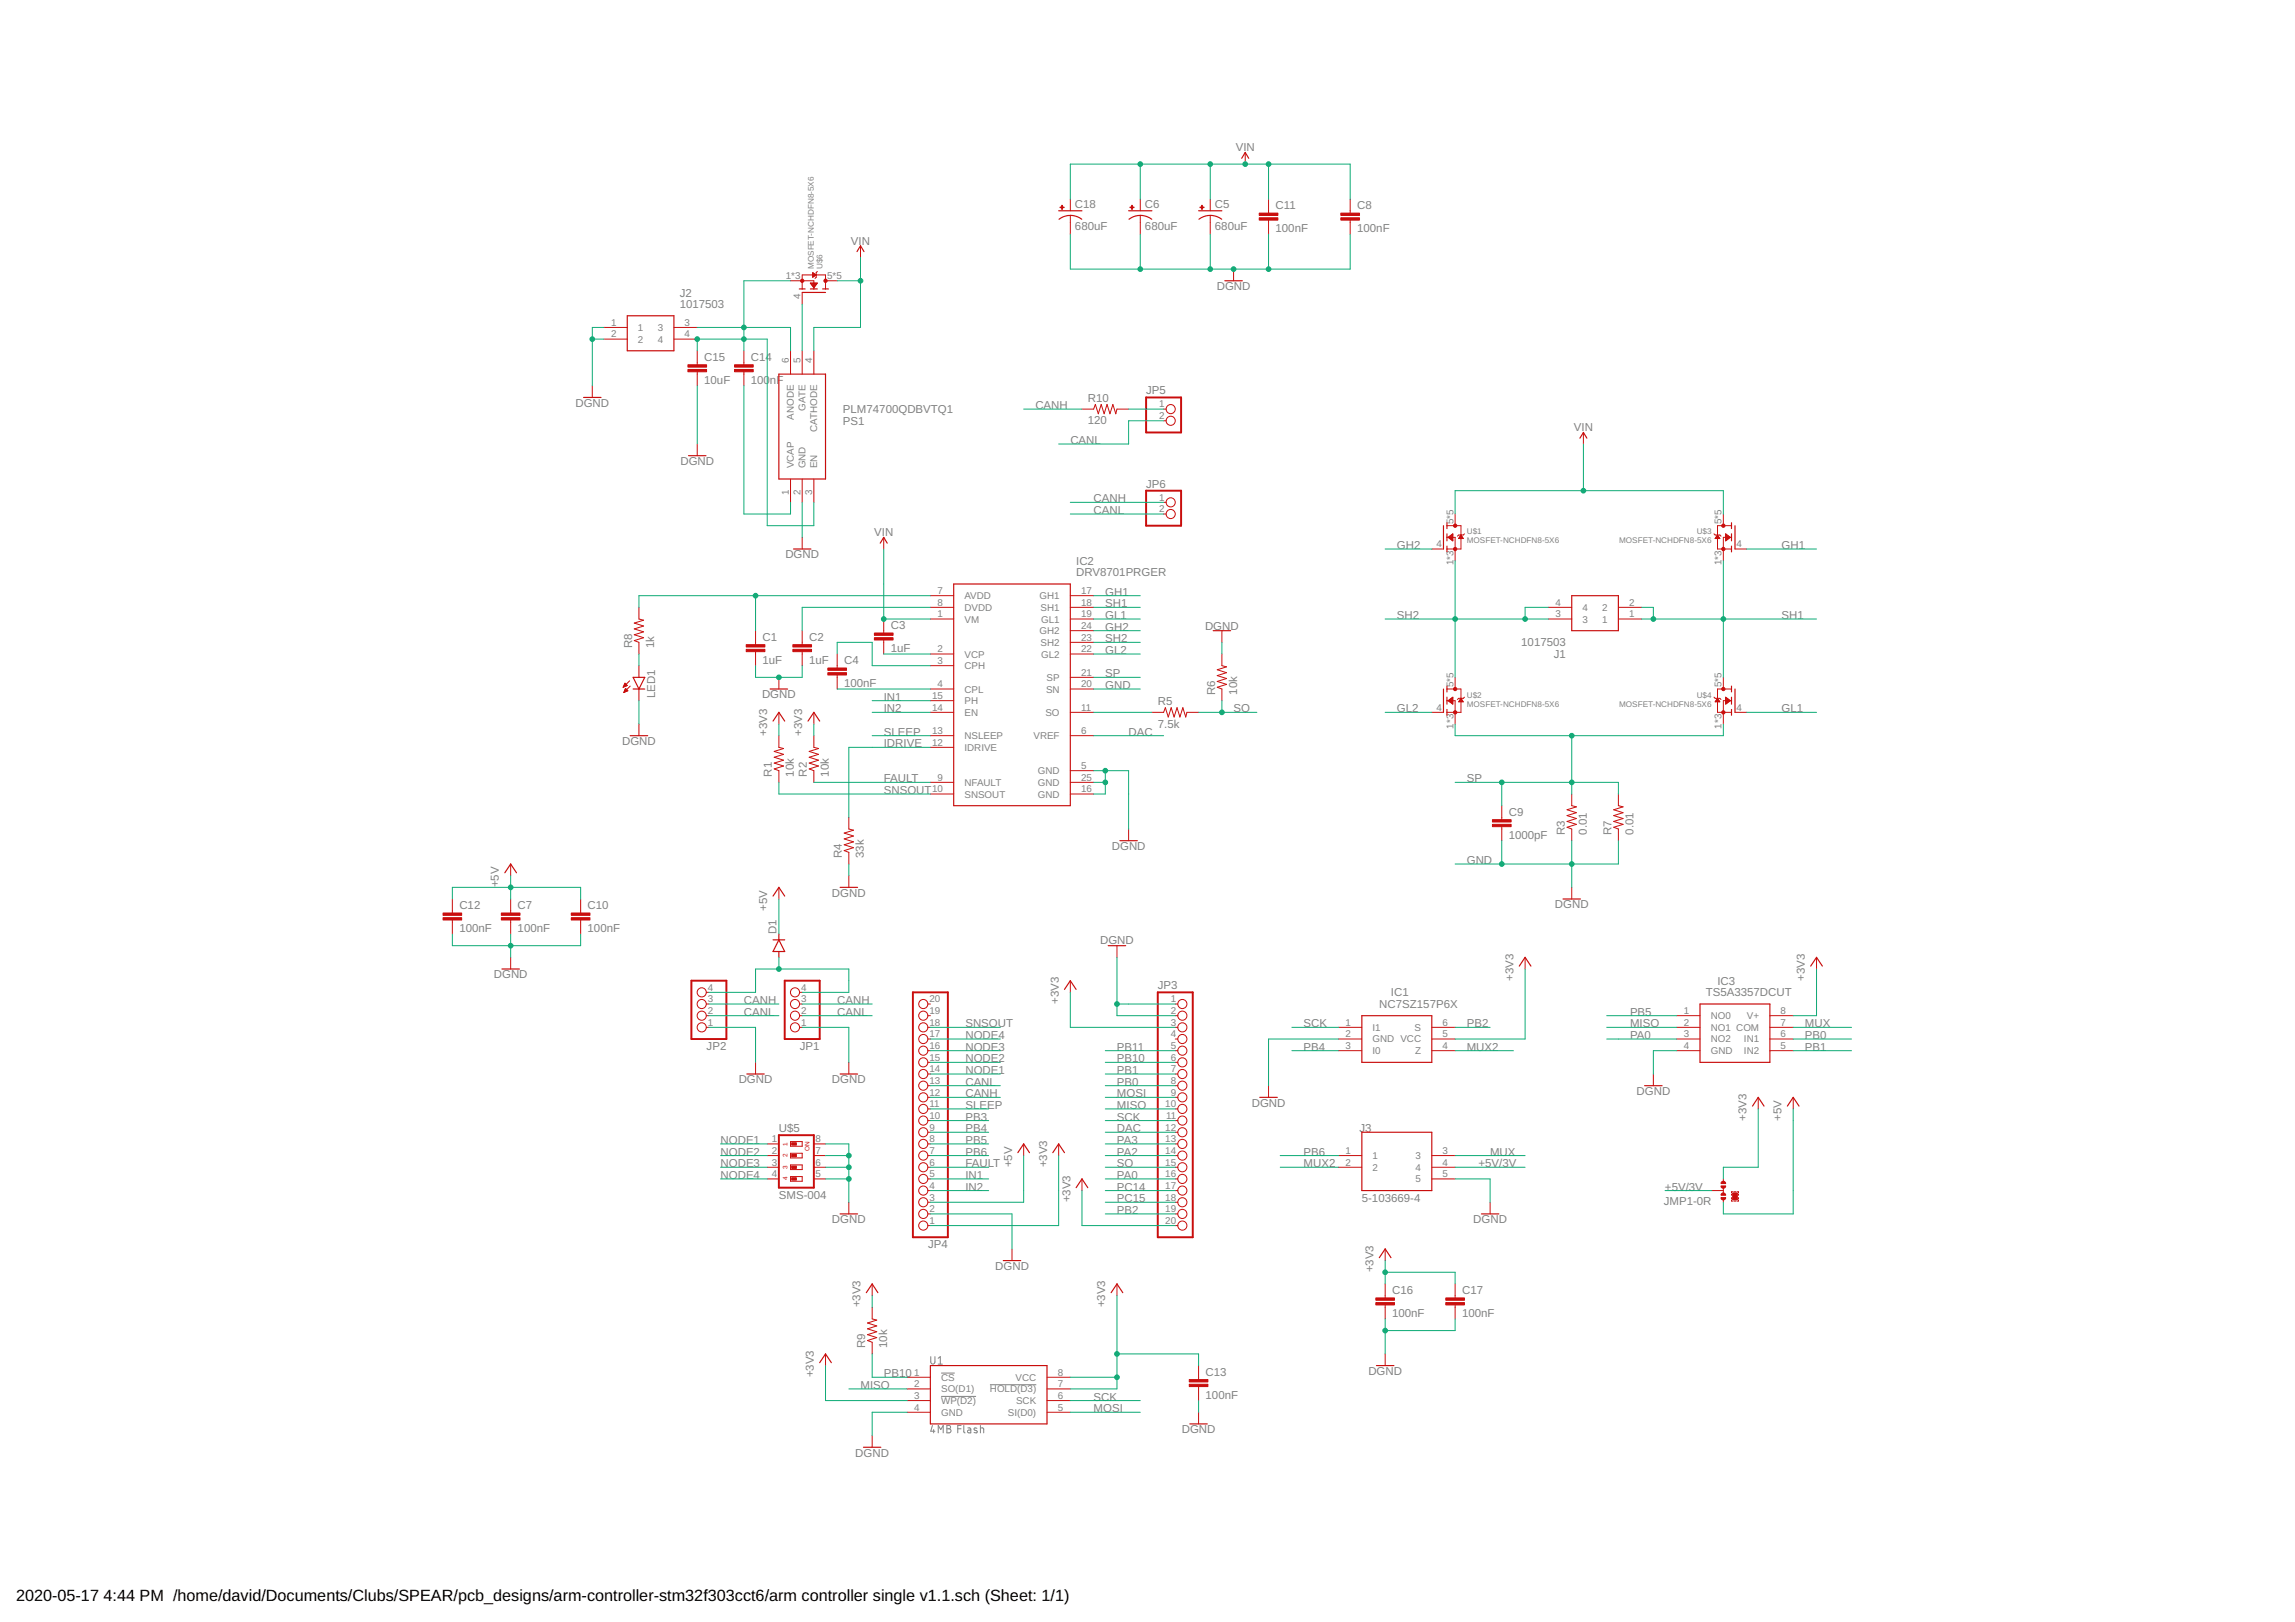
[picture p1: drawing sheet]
<svg xmlns="http://www.w3.org/2000/svg" width="500mm" height="353mm" viewBox="0 0 500 353" stroke-linecap="round" stroke-linejoin="round" font-family="sans-serif">
<defs><g id="words">
<g font-size="3.5">
<text x="3.5" y="348.6">2020-05-17</text>
<text x="22.6" y="348.6">4:44 PM /home/david/Documents/Clubs/SPEAR/pcb_designs/arm-controller-stm32f303cct6/arm controller single v1.1.sch (Sheet: 1/1)</text>
</g>
<g font-size="2.5" fill="#808080">
<text x="269.2" y="32.9">VIN</text>
<text x="234.2" y="45.3">C18</text>
<text x="249.4" y="45.3">C6</text>
<text x="264.6" y="45.3">C5</text>
<text x="277.8" y="45.5">C11</text>
<text x="295.6" y="45.5">C8</text>
<text x="185.3" y="53.3">VIN</text>
<text x="234.2" y="50.1">680uF</text>
<text x="249.4" y="50.1">680uF</text>
<text x="264.6" y="50.1">680uF</text>
<text x="277.8" y="50.6">100nF</text>
<text x="295.6" y="50.6">100nF</text>
<text x="148.1" y="64.6">J2</text>
<text x="265" y="63.2">DGND</text>
<text x="148.1" y="67.1">1017503</text>
<text x="153.4" y="83.6">10uF</text>
<text x="153.4" y="78.5">C15</text>
<text x="163.5" y="83.6">100</text>
<text x="163.5" y="78.5">C14</text>
<text x="167.7" y="83.6">nF</text>
<text x="125.3" y="88.6">DGND</text>
<text x="183.6" y="89.9">PLM74700QDBVTQ1</text>
<text x="225.5" y="89.1">CANH</text>
<text x="236.9" y="87.6">R10</text>
<text x="249.6" y="85.9">JP5</text>
<text x="183.6" y="92.5">PS1</text>
<text x="236.9" y="92.4">120</text>
<text x="342.8" y="93.9">VIN</text>
<text x="148.2" y="101.3">DGND</text>
<text x="233.1" y="96.7">CANL</text>
<text x="249.6" y="106.2">JP6</text>
<text x="238.2" y="109.4">CANH</text>
<text x="238.2" y="111.9">CANL</text>
<text x="190.4" y="116.7">VIN</text>
<text x="304.2" y="119.5">GH2</text>
<text x="388.1" y="119.5">GH1</text>
<text x="171.1" y="121.6">DGND</text>
<text x="234.4" y="125.5">DRV8701PRGER</text>
<text x="234.4" y="123">IC2</text>
<text x="240.8" y="129.7">GH1</text>
<text x="194" y="136.9">C3</text>
<text x="240.8" y="137.3">GH2</text>
<text x="240.8" y="134.8">GL1</text>
<text x="240.8" y="132.2">SH1</text>
<text x="262.5" y="137.1">DGND</text>
<text x="304.2" y="134.8">SH2</text>
<text x="388.1" y="134.8">SH1</text>
<text x="137.7" y="141.1" transform="rotate(-90 137.7 141.1)">R8</text>
<text x="142.5" y="141.1" transform="rotate(-90 142.5 141.1)">1k</text>
<text x="166.1" y="139.5">C1</text>
<text x="176.2" y="139.5">C2</text>
<text x="194" y="142">1uF</text>
<text x="240.8" y="142.4">GL2</text>
<text x="240.8" y="139.9">SH2</text>
<text x="331.4" y="140.7">1017503</text>
<text x="338.4" y="143.3">J1</text>
<text x="166.1" y="144.6">1uF</text>
<text x="176.2" y="144.6">1uF</text>
<text x="183.9" y="149.6">100nF</text>
<text x="183.9" y="144.6">C4</text>
<text x="240.8" y="147.5">SP</text>
<text x="142.7" y="152" transform="rotate(-90 142.7 152)">LED1</text>
<text x="166" y="152">DGND</text>
<text x="192.5" y="152.6">IN1</text>
<text x="192.5" y="155.1">IN2</text>
<text x="240.8" y="150">GND</text>
<text x="252.2" y="153.6">R5</text>
<text x="264.7" y="151.3" transform="rotate(-90 264.7 151.3)">R6</text>
<text x="268.7" y="155.1">SO</text>
<text x="269.5" y="151.3" transform="rotate(-90 269.5 151.3)">10k</text>
<text x="304.2" y="155.1">GL2</text>
<text x="388.1" y="155.1">GL1</text>
<text x="167.1" y="160.2" transform="rotate(-90 167.1 160.2)">+3V3</text>
<text x="174.7" y="160.2" transform="rotate(-90 174.7 160.2)">+3V3</text>
<text x="192.5" y="160.2">SLEEP</text>
<text x="245.8" y="160.2">DAC</text>
<text x="252.2" y="158.4">7.5k</text>
<text x="135.5" y="162.2">DGND</text>
<text x="192.5" y="162.7">IDRIVE</text>
<text x="168.1" y="169.1" transform="rotate(-90 168.1 169.1)">R1</text>
<text x="172.9" y="169.1" transform="rotate(-90 172.9 169.1)">10k</text>
<text x="175.8" y="169.1" transform="rotate(-90 175.8 169.1)">R2</text>
<text x="180.6" y="169.1" transform="rotate(-90 180.6 169.1)">10k</text>
<text x="192.5" y="170.3">FAULT</text>
<text x="192.5" y="172.9">SNSOUT</text>
<text x="319.5" y="170.3">SP</text>
<text x="328.6" y="177.6">C9</text>
<text x="242.2" y="185.1">DGND</text>
<text x="328.6" y="182.6">1000pF</text>
<text x="340.8" y="181.8" transform="rotate(-90 340.8 181.8)">R3</text>
<text x="345.6" y="181.8" transform="rotate(-90 345.6 181.8)">0.01</text>
<text x="351" y="181.8" transform="rotate(-90 351 181.8)">R7</text>
<text x="355.8" y="181.8" transform="rotate(-90 355.8 181.8)">0.01</text>
<text x="183.4" y="186.8" transform="rotate(-90 183.4 186.8)">R4</text>
<text x="188.2" y="186.8" transform="rotate(-90 188.2 186.8)">33k</text>
<text x="319.5" y="188.1">GND</text>
<text x="100.1" y="197.9">C12</text>
<text x="108.7" y="193.2" transform="rotate(-90 108.7 193.2)">+5V</text>
<text x="112.8" y="197.9">C7</text>
<text x="128" y="197.9">C10</text>
<text x="181.2" y="195.2">DGND</text>
<text x="338.7" y="197.8">DGND</text>
<text x="100.1" y="203">100nF</text>
<text x="112.8" y="203">100nF</text>
<text x="128" y="203">100nF</text>
<text x="167.1" y="198.3" transform="rotate(-90 167.1 198.3)">+5V</text>
<text x="169.2" y="203.3" transform="rotate(-90 169.2 203.3)">D1</text>
<text x="239.6" y="205.6">DGND</text>
<text x="107.6" y="213">DGND</text>
<text x="252.2" y="215.4">JP3</text>
<text x="329.6" y="213.5" transform="rotate(-90 329.6 213.5)">+3V3</text>
<text x="374.1" y="214.4">IC3</text>
<text x="393.1" y="213.5" transform="rotate(-90 393.1 213.5)">+3V3</text>
<text x="162" y="218.6">CANH</text>
<text x="162" y="221.1">CANL</text>
<text x="182.3" y="218.6">CANH</text>
<text x="182.3" y="221.1">CANL</text>
<text x="230.6" y="218.6" transform="rotate(-90 230.6 218.6)">+3V3</text>
<text x="300.4" y="219.5">NC7SZ157P6X</text>
<text x="303" y="216.9">IC1</text>
<text x="355" y="221.1">PB5</text>
<text x="371.6" y="216.9">TS5A3357DCUT</text>
<text x="210.3" y="226.2">NODE4</text>
<text x="210.3" y="223.7">SNSOUT</text>
<text x="283.9" y="223.7">SCK</text>
<text x="319.5" y="223.7">PB2</text>
<text x="355" y="226.2">PA0</text>
<text x="355" y="223.7">MISO</text>
<text x="393.1" y="223.7">MUX</text>
<text x="393.1" y="226.2">PB0</text>
<text x="153.9" y="228.6">JP2</text>
<text x="174.2" y="228.6">JP1</text>
<text x="210.3" y="233.8">NODE1</text>
<text x="210.3" y="231.3">NODE2</text>
<text x="210.3" y="228.7">NODE3</text>
<text x="243.3" y="233.8">PB1</text>
<text x="243.3" y="231.3">PB10</text>
<text x="243.3" y="228.7">PB11</text>
<text x="283.9" y="228.7">PB4</text>
<text x="319.5" y="228.7">MUX2</text>
<text x="393.1" y="228.7">PB1</text>
<text x="160.9" y="235.9">DGND</text>
<text x="181.2" y="235.9">DGND</text>
<text x="210.3" y="238.9">CANH</text>
<text x="210.3" y="236.4">CANL</text>
<text x="243.3" y="238.9">MOSI</text>
<text x="243.3" y="236.4">PB0</text>
<text x="356.5" y="238.4">DGND</text>
<text x="210.3" y="241.4">SLEEP</text>
<text x="210.3" y="244">PB3</text>
<text x="243.3" y="244">SCK</text>
<text x="243.3" y="241.4">MISO</text>
<text x="272.6" y="240.9">DGND</text>
<text x="380.4" y="244" transform="rotate(-90 380.4 244)">+3V3</text>
<text x="388.1" y="244" transform="rotate(-90 388.1 244)">+5V</text>
<text x="156.9" y="249.1">NODE1</text>
<text x="156.9" y="251.6">NODE2</text>
<text x="169.6" y="246.5">U$5</text>
<text x="210.3" y="246.5">PB4</text>
<text x="210.3" y="249.1">PB5</text>
<text x="210.3" y="251.6">PB6</text>
<text x="243.3" y="251.6">PA2</text>
<text x="243.3" y="249.1">PA3</text>
<text x="243.3" y="246.5">DAC</text>
<text x="283.9" y="251.6">PB6</text>
<text x="296.1" y="246.5">J</text>
<text x="297.4" y="246.5">3</text>
<text x="324.6" y="251.6">MUX</text>
<text x="156.9" y="254.1">NODE3</text>
<text x="156.9" y="256.7">NODE4</text>
<text x="210.3" y="256.7">IN1</text>
<text x="210.3" y="254.1">FAULT</text>
<text x="220.4" y="254.1" transform="rotate(-90 220.4 254.1)">+5V</text>
<text x="228.1" y="254.1" transform="rotate(-90 228.1 254.1)">+3V3</text>
<text x="243.3" y="254.1">SO</text>
<text x="243.3" y="256.7">PA0</text>
<text x="283.9" y="254.1">MUX2</text>
<text x="322" y="254.1">+5V/3V</text>
<text x="169.6" y="261.1">SMS-004</text>
<text x="210.3" y="259.2">IN2</text>
<text x="233.1" y="261.8" transform="rotate(-90 233.1 261.8)">+3V3</text>
<text x="243.3" y="259.2">PC14</text>
<text x="243.3" y="261.8">PC15</text>
<text x="296.6" y="261.8">5-103669-4</text>
<text x="362.4" y="262.3">JMP1-0R</text>
<text x="362.7" y="259.2">+5V/3V</text>
<text x="181.2" y="266.3">DGND</text>
<text x="243.3" y="264.3">PB2</text>
<text x="320.9" y="266.3">DGND</text>
<text x="202.2" y="271.8">JP4</text>
<text x="216.8" y="276.5">DGND</text>
<text x="299.2" y="277" transform="rotate(-90 299.2 277)">+3V3</text>
<text x="303.2" y="281.7">C16</text>
<text x="318.5" y="281.7">C17</text>
<text x="187.4" y="284.6" transform="rotate(-90 187.4 284.6)">+3V3</text>
<text x="240.8" y="284.6" transform="rotate(-90 240.8 284.6)">+3V3</text>
<text x="303.2" y="286.8">100nF</text>
<text x="318.5" y="286.8">100nF</text>
<text x="188.5" y="293.5" transform="rotate(-90 188.5 293.5)">R9</text>
<text x="193.3" y="293.5" transform="rotate(-90 193.3 293.5)">10k</text>
<text x="177.3" y="299.8" transform="rotate(-90 177.3 299.8)">+3V3</text>
<text x="192.5" y="299.8">PB10</text>
<text x="262.6" y="299.5">C13</text>
<text x="298" y="299.3">DGND</text>
<text x="187.4" y="302.4">MISO</text>
<text x="238.2" y="304.9">SCK</text>
<text x="262.6" y="304.5">100nF</text>
<text x="238.2" y="307.5">MOSI</text>
<text x="186.3" y="317.1">DGND</text>
<text x="257.4" y="312">DGND</text>
</g>
<g font-size="2.1" fill="#808080">
<text x="171.1" y="60.8">1*3</text>
<text x="174.4" y="65.2" transform="rotate(-90 174.4 65.2)">4</text>
<text x="180.2" y="60.8">5*5</text>
<text x="133.1" y="70.9">1</text>
<text x="149.1" y="70.9">3</text>
<text x="133.1" y="73.5">2</text>
<text x="139" y="72">1</text>
<text x="139" y="74.6">2</text>
<text x="143.3" y="72">3</text>
<text x="143.3" y="74.6">4</text>
<text x="149.1" y="73.5">4</text>
<text x="171.8" y="79.1" transform="rotate(-90 171.8 79.1)">6</text>
<text x="174.4" y="79.1" transform="rotate(-90 174.4 79.1)">5</text>
<text x="176.9" y="79.1" transform="rotate(-90 176.9 79.1)">4</text>
<text x="175.5" y="89.4" transform="rotate(-90 175.5 89.4)">GATE</text>
<text x="252.5" y="88.7">1</text>
<text x="172.9" y="91.4" transform="rotate(-90 172.9 91.4)">ANODE</text>
<text x="178" y="94.1" transform="rotate(-90 178 94.1)">CATHODE</text>
<text x="252.5" y="91.2">2</text>
<text x="172.9" y="102" transform="rotate(-90 172.9 102)">VCAP</text>
<text x="175.5" y="102" transform="rotate(-90 175.5 102)">GND</text>
<text x="178" y="102" transform="rotate(-90 178 102)">EN</text>
<text x="171.8" y="107.8" transform="rotate(-90 171.8 107.8)">1</text>
<text x="174.4" y="107.8" transform="rotate(-90 174.4 107.8)">2</text>
<text x="176.9" y="107.8" transform="rotate(-90 176.9 107.8)">3</text>
<text x="252.5" y="109">1</text>
<text x="252.5" y="111.6">2</text>
<text x="312.9" y="119.2">4</text>
<text x="316.6" y="114.1" transform="rotate(-90 316.6 114.1)">5*5</text>
<text x="375" y="114.1" transform="rotate(-90 375 114.1)">5*5</text>
<text x="378.3" y="119.2">4</text>
<text x="316.6" y="123.1" transform="rotate(-90 316.6 123.1)">1*3</text>
<text x="375" y="123.1" transform="rotate(-90 375 123.1)">1*3</text>
<text x="204.2" y="129.3">7</text>
<text x="204.2" y="131.9">8</text>
<text x="210.1" y="130.5">AVDD</text>
<text x="226.4" y="130.5">GH1</text>
<text x="235.5" y="131.9">18</text>
<text x="235.5" y="129.3">17</text>
<text x="338.8" y="131.9">4</text>
<text x="354.8" y="131.9">2</text>
<text x="204.2" y="134.4">1</text>
<text x="210.1" y="135.5">VM</text>
<text x="210.1" y="133">DVDD</text>
<text x="226.7" y="133">SH1</text>
<text x="226.8" y="135.5">GL1</text>
<text x="235.5" y="137">24</text>
<text x="235.5" y="134.4">19</text>
<text x="338.8" y="134.4">3</text>
<text x="344.7" y="135.5">3</text>
<text x="344.7" y="133">4</text>
<text x="349" y="135.5">1</text>
<text x="349" y="133">2</text>
<text x="354.8" y="134.4">1</text>
<text x="204.2" y="142">2</text>
<text x="210.1" y="143.2">VCP</text>
<text x="226.4" y="138.1">GH2</text>
<text x="226.7" y="140.6">SH2</text>
<text x="226.8" y="143.2">GL2</text>
<text x="235.5" y="139.5">23</text>
<text x="235.5" y="142">22</text>
<text x="204.2" y="144.6">3</text>
<text x="204.2" y="149.7">4</text>
<text x="210.1" y="145.7">CPH</text>
<text x="227.9" y="148.2">SP</text>
<text x="235.5" y="147.1">21</text>
<text x="235.5" y="149.7">20</text>
<text x="316.6" y="149.7" transform="rotate(-90 316.6 149.7)">5*5</text>
<text x="375" y="149.7" transform="rotate(-90 375 149.7)">5*5</text>
<text x="203" y="152.2">15</text>
<text x="203" y="154.7">14</text>
<text x="210.1" y="150.8">CPL</text>
<text x="210.1" y="153.3">PH</text>
<text x="210.1" y="155.9">EN</text>
<text x="227.7" y="155.9">SO</text>
<text x="227.8" y="150.8">SN</text>
<text x="235.5" y="154.7">11</text>
<text x="312.9" y="154.7">4</text>
<text x="378.3" y="154.7">4</text>
<text x="203" y="159.8">13</text>
<text x="210.1" y="160.9">NSLEEP</text>
<text x="225.1" y="160.9">VREF</text>
<text x="235.5" y="159.8">6</text>
<text x="316.6" y="158.7" transform="rotate(-90 316.6 158.7)">1*3</text>
<text x="375" y="158.7" transform="rotate(-90 375 158.7)">1*3</text>
<text x="203" y="162.4">12</text>
<text x="210.1" y="163.5">IDRIVE</text>
<text x="235.5" y="167.4">5</text>
<text x="203" y="172.5">10</text>
<text x="204.2" y="170">9</text>
<text x="210.1" y="171.1">NFAULT</text>
<text x="210.1" y="173.6">SNSOUT</text>
<text x="226.1" y="168.6">GND</text>
<text x="226.1" y="173.6">GND</text>
<text x="226.1" y="171.1">GND</text>
<text x="235.5" y="172.5">16</text>
<text x="235.5" y="170">25</text>
<text x="154.2" y="215.7">4</text>
<text x="174.5" y="215.7">4</text>
<text x="154.2" y="220.8">2</text>
<text x="154.2" y="218.2">3</text>
<text x="174.5" y="220.8">2</text>
<text x="174.5" y="218.2">3</text>
<text x="202.5" y="220.8">19</text>
<text x="202.5" y="218.2">20</text>
<text x="255" y="218.2">1</text>
<text x="255" y="220.8">2</text>
<text x="366.8" y="220.8">1</text>
<text x="372.6" y="221.9">NO0</text>
<text x="380.5" y="221.9">V+</text>
<text x="387.9" y="220.8">8</text>
<text x="154.2" y="223.3">1</text>
<text x="174.5" y="223.3">1</text>
<text x="202.5" y="225.8">17</text>
<text x="202.5" y="223.3">18</text>
<text x="255" y="223.3">3</text>
<text x="255" y="225.8">4</text>
<text x="293.1" y="223.3">1</text>
<text x="293.1" y="225.8">2</text>
<text x="299" y="224.4">I1</text>
<text x="299" y="227">GND VCC</text>
<text x="308.1" y="224.4">S</text>
<text x="314.2" y="223.3">6</text>
<text x="314.2" y="225.8">5</text>
<text x="366.8" y="223.3">2</text>
<text x="366.8" y="225.8">3</text>
<text x="372.6" y="224.4">NO1 COM</text>
<text x="372.6" y="227">NO2</text>
<text x="379.9" y="227">IN1</text>
<text x="387.9" y="223.3">7</text>
<text x="387.9" y="225.8">6</text>
<text x="202.5" y="233.5">14</text>
<text x="202.5" y="230.9">15</text>
<text x="202.5" y="228.4">16</text>
<text x="255" y="228.4">5</text>
<text x="255" y="230.9">6</text>
<text x="255" y="233.5">7</text>
<text x="293.1" y="228.4">3</text>
<text x="299" y="229.5">I0</text>
<text x="308.2" y="229.5">Z</text>
<text x="314.2" y="228.4">4</text>
<text x="366.8" y="228.4">4</text>
<text x="372.6" y="229.5">GND</text>
<text x="379.9" y="229.5">IN2</text>
<text x="387.9" y="228.4">5</text>
<text x="202.5" y="238.5">12</text>
<text x="202.5" y="236">13</text>
<text x="255" y="236">8</text>
<text x="255" y="238.5">9</text>
<text x="202.5" y="243.6">10</text>
<text x="202.5" y="241.1">11</text>
<text x="253.8" y="241.1">10</text>
<text x="254" y="243.6">11</text>
<text x="168.1" y="248.7">1</text>
<text x="168.1" y="251.2">2</text>
<text x="177.6" y="251.2">7</text>
<text x="177.6" y="248.7">8</text>
<text x="202.5" y="251.2">7</text>
<text x="202.5" y="248.7">8</text>
<text x="202.5" y="246.2">9</text>
<text x="253.8" y="246.2">12</text>
<text x="253.8" y="248.7">13</text>
<text x="253.8" y="251.2">14</text>
<text x="293.1" y="251.2">1</text>
<text x="314.2" y="251.2">3</text>
<text x="168.1" y="253.8">3</text>
<text x="168.1" y="256.3">4</text>
<text x="177.6" y="256.3">5</text>
<text x="177.6" y="253.8">6</text>
<text x="202.5" y="256.3">5</text>
<text x="202.5" y="253.8">6</text>
<text x="253.8" y="253.8">15</text>
<text x="253.8" y="256.3">16</text>
<text x="293.1" y="253.8">2</text>
<text x="299" y="252.4">1</text>
<text x="299" y="254.9">2</text>
<text x="308.3" y="252.4">3</text>
<text x="308.3" y="254.9">4</text>
<text x="308.3" y="257.4">5</text>
<text x="314.2" y="253.8">4</text>
<text x="314.2" y="256.3">5</text>
<text x="202.5" y="263.9">2</text>
<text x="202.5" y="261.4">3</text>
<text x="202.5" y="258.9">4</text>
<text x="253.8" y="258.9">17</text>
<text x="253.8" y="261.4">18</text>
<text x="253.8" y="263.9">19</text>
<text x="202.5" y="266.5">1</text>
<text x="253.8" y="266.5">20</text>
<text x="199.1" y="299.5">1</text>
<text x="230.4" y="299.5">8</text>
<text x="199.1" y="304.6">3</text>
<text x="199.1" y="302">2</text>
<text x="205" y="300.6">CS</text>
<text x="205" y="305.7">WP(D2)</text>
<text x="205" y="303.2">SO(D1)</text>
<text x="215.6" y="303.2">HOLD(D3)</text>
<text x="221.2" y="300.6">VCC</text>
<text x="221.3" y="305.7">SCK</text>
<text x="230.4" y="302">7</text>
<text x="230.4" y="304.6">6</text>
<text x="199.1" y="307.1">4</text>
<text x="205" y="308.2">GND</text>
<text x="219.5" y="308.2">SI(D0)</text>
<text x="230.4" y="307.1">5</text>
</g>
<g font-size="1.8" fill="#808080">
<text x="177.3" y="58.6" transform="rotate(-90 177.3 58.6)">MOSFET-NCHDFN8-5X6</text>
<text x="179.2" y="58.6" transform="rotate(-90 179.2 58.6)">U$6</text>
<text x="319.5" y="118.3">MOSFET-NCHDFN8-5X6</text>
<text x="319.5" y="116.4">U$1</text>
<text x="352.7" y="118.3">MOSFET-NCHDFN8-5X6</text>
<text x="369.6" y="116.4">U$3</text>
<text x="319.5" y="153.8">MOSFET-NCHDFN8-5X6</text>
<text x="319.5" y="151.9">U$2</text>
<text x="352.7" y="153.8">MOSFET-NCHDFN8-5X6</text>
<text x="369.6" y="151.9">U$4</text>
</g>
<g font-size="1.4" fill="#c90d0c">
<text x="171.5" y="251.9" transform="rotate(-90 171.5 251.9)">2</text>
<text x="171.5" y="249.6" transform="rotate(-90 171.5 249.6)">1</text>
<text x="176.4" y="250.5" transform="rotate(-90 176.4 250.5)">ON</text>
<text x="171.5" y="257" transform="rotate(-90 171.5 257)">4</text>
<text x="171.5" y="254.4" transform="rotate(-90 171.5 254.4)">3</text>
</g>
</g></defs>
<g fill="none" stroke="#808080" stroke-width=".22">
<path d="M202.7 295.4v1.1a.46 .46 0 0 0 .5 .5 .46 .46 0 0 0 .4-.5v-1.1M204.3 295.7l.5-.3v1.6M204.3 297h1M205 298.9h3M203.1 310.3l-.4 1.3h.9M203.4 311.2v.8M204.4 312v-1.7l.5 .9 .5-.9v1.7M205 304h7.6M206.2 310.3h.5a.36 .36 0 0 1 .4 .4 .36 .36 0 0 1-.4 .4 .44 .44 0 0 1 .5 .4 .44 .44 0 0 1-.5 .5h-.5zM206.2 311.1h.5M208.6 311.1h.7M209.3 310.3h-.7v1.7"/>
<path d="M209.9 310.3v1.4l.3 .3M210.8 310.9l.6 .1 .1 1-.7-.2v-.4l.7-.1M212.8 311l-.4-.1-.3 .2 .6 .4 .2 .3-.3 .2-.4-.1M213.6 310.9l.6 .1 .1 1M213.6 310.3v1.7M215.6 301.5h10.1"/>
</g>
<g fill="none" stroke="#c90d0c" stroke-width=".22">
<path d="M271.2 33.2v2.5M177 59.4l.8 .5-.8 .5zM177 59.9h.6M177 59.8h.7M177 59.7h.5M177 59.6h.4M177 59.5h.2M178 59.1l-.2 .3v1l-.3 .2M187.4 53.5v2.5M233.1 43.3v2.6M233.1 46.9v4.1M248.4 43.3v2.6"/>
<path d="M248.4 46.9v4.1M263.6 43.3v2.6M263.6 46.9v4.1M268.7 58.6v2.5M276.3 43.3v3.1M276.3 47.9v3.1M294.1 43.3v3.1M294.1 47.9v3.1M131.6 71.3h5M131.6 73.8h5M146.8 71.3h5.1M146.8 73.8h5.1"/>
<path d="M151.9 76.4v3M162 76.4v3M172.2 76.4v5M172.2 61.1h5.1v1.8M174.7 62.9v-3h5.1v3M174.7 63.7v2.5M174.7 76.4v5M176.5 61.6h1.5l-.7 1.1zM176.6 61.8h1.3M176.7 61.9h1.1M176.8 62h1M176.9 62.1h.8"/>
<path d="M177 62.2h.6M177 60.3h.1M177 60.2h.3M177 60.1h.5M177 62.4h.5M177.1 62.5h.3M177.2 62.6h.1M177.3 76.4v5M179.8 61.1h2.6M129 84v2.5M151.9 80.9v3.1M151.9 96.7v2.5"/>
<path d="M162 80.9v3.1M235.7 89.1h2.5l.4-1 .6 2 .7-2 .6 2 .6-2 .7 2 .6-2 .6 2 .3-1h2.5M253.4 89.1h.6M253.4 91.6h.6M344.9 94.1v2.6M172.2 104.3v5.1M174.7 104.3v5.1M174.7 117v2.5M177.3 104.3v5.1M192.5 117v2.5M253.4 109.4h.6M253.4 111.9h.6"/>
<path d="M311.9 119.5h2.5M315.2 117h1.7v5.1M315.2 114.4h3v5.1h-3M315.4 117h1M315.4 117l1-.8v1.6zM315.6 116.9h.8M315.6 117.1h.8M315.7 116.8h.7M315.8 117.2h.6M315.9 116.6h.5M315.9 117.4h.5M316.1 116.5h.3"/>
<path d="M316.1 117.5h.3M316.2 116.4h.2M316.2 117.6h.2M316.4 116.3h.1M316.4 117.7h.1M316.9 111.9v2.5M317.8 117.1h.8M317.9 117h.7M317.9 116.9h.6M318 116.8h.4M318.1 116.6h.2M318.2 116.5h.1"/>
<path d="M318.2 116.5l.5 .7h-1zM319 116.2l-.3 .3h-1l-.2 .2M373.3 116.2l.3 .3h1l.3 .2M373.7 117.1h.8M373.7 117h.7M373.8 116.9h.6M373.9 116.8h.4M374 116.6h.2M374.1 116.5h.1M374.1 116.5l.5 .7h-1zM375.4 111.9v2.5M375.9 117.2h.7"/>
<path d="M375.9 117.1h.8M375.9 117h1M375.9 116.9h.8M375.9 116.8h.7M375.9 116.6h.5M375.9 116.5h.4M375.9 117.7h.1M375.9 117.6h.2M375.9 117.5h.3M375.9 117.4h.5M375.9 116.4h.2M375.9 116.3h.1"/>
<path d="M375.9 116.2l1 .8-1 .8zM377.1 117h-1.7v5.1M377.1 114.4h-3v5.1h3M377.9 119.5h2.5M139.2 132.2v2.6l1 .2-2 .7 2 .6-2 .6 2 .7-2 .6 2 .6-2 .7 1 .3v2.6M164.6 137.3v3.1M174.7 137.3v3.1M192.5 134.8v3M192.5 139.3v3.1M202.6 134.8h5.1M202.6 129.7h5.1M202.6 132.2h5.1"/>
<path d="M233.1 134.8h5.1M233.1 129.7h5.1M233.1 132.2h5.1M233.1 137.3h5.1M233.1 139.8h5.1M266.1 137.3v2.5M337.3 134.8h5M337.3 132.2h5M352.5 134.8h5.1M352.5 132.2h5.1M135.8 149.6h.1M135.8 149.5h.3"/>
<path d="M135.9 149.3h.5M135.9 149.2h.7M135.9 150.7h.2M136 149.1h.5M136 150.5h.4M136 149h.4M136 150.4h.7M136.1 150.3h.6M136.1 148.8h.1M136.1 148.7l.5 .5-.9 .4zM136.1 150.2h.4M136.2 150.1h.2"/>
<path d="M136.2 149.9h.1M136.2 149.9l.6 .5-.9 .4zM137.1 148.2l-1.4 1.4M137.3 149.4l-1.4 1.4M139.2 144.9v2.6M139.2 150v2.5M139.2 157.6v2.6M164.6 141.9v3M169.7 147.5v2.5M169.7 155.1v2.5M174.7 141.9v3M177.3 155.1v2.5"/>
<path d="M182.4 142.4v3M182.4 147v3M202.6 142.4h5.1M202.6 144.9h5.1M202.6 150h5.1M202.6 155.1h5.1M202.6 152.5h5.1M233.1 142.4h5.1M233.1 150h5.1M233.1 155.1h5.1M233.1 147.5h5.1M250.9 155.1h2.5l.4-1 .7 2 .6-2 .6 2 .7-2 .6 2 .6-2 .7 2 .2-1h2.6"/>
<path d="M266.1 142.4v2.5l1.1 .3-2.1 .6 2.1 .7-2.1 .6 2.1 .6-2.1 .7 2.1 .6-2.1 .6 1 .4v2.5M311.9 155.1h2.5M315.2 150h3v5.1h-3M315.2 152.5h1.7v5.1M315.4 152.5l1-.7v1.5zM315.5 152.6h.9M315.5 152.5h.9M315.6 152.7h.8M315.7 152.4h.7M315.8 152.8h.6M315.8 152.2h.6M316 153h.4"/>
<path d="M316 152.1h.4M316.1 153.1h.3M316.2 152h.2M316.3 153.2h.1M316.3 151.9h.1M316.9 147.5v2.5M317.8 152.7h.9M317.9 152.6h.7M317.9 152.5h.6M318 152.4h.4M318.1 152.2h.2M318.2 152.1h.1"/>
<path d="M318.2 152l.5 .8h-1zM319 151.8l-.3 .2h-1l-.2 .3M373.3 151.8l.3 .2h1l.3 .3M373.7 152.7h.8M373.7 152.6h.8M373.8 152.5h.6M373.9 152.4h.4M374 152.2h.2M374.1 152.1h.1M374.1 152l.5 .8h-1zM375.4 147.5v2.5M375.9 152.8h.6"/>
<path d="M375.9 152.7h.8M375.9 152.6h.9M375.9 152.5h.9M375.9 152.4h.7M375.9 152.2h.5M375.9 152.1h.4M375.9 153.2h.1M375.9 153.1h.3M375.9 153h.4M375.9 152h.2M375.9 151.9h.1M375.9 151.8l1 .7-1 .8z"/>
<path d="M377.1 152.5h-1.7v5.1M377.1 150h-3v5.1h3M377.9 155.1h2.5M169.7 160.2v2.5l1 .3-2.1 .6 2.1 .6-2.1 .7 2.1 .6-2.1 .6 2.1 .7-2.1 .6 1.1 .4v2.5M177.3 160.2v2.5l1 .3-2 .6 2 .6-2 .7 2 .6-2 .6 2 .7-2 .6 1 .4v2.5M184.9 177.9v2.6l1 .2-2 .7 2 .6-2 .6 2 .7-2 .6 2 .7-2 .6 1 .4v2.5M202.6 160.2h5.1M202.6 170.3h5.1M202.6 172.9h5.1M202.6 162.7h5.1M233.1 167.8h5.1M233.1 160.2h5.1"/>
<path d="M233.1 170.3h5.1M233.1 172.9h5.1M327.1 175.4v3.1M327.1 180v3M342.3 172.9v2.5l1.1 .3-2.1 .6 2.1 .6-2.1 .7 2.1 .6-2.1 .6 2.1 .7-2.1 .6 1 .4v2.5M352.5 172.9v2.5l1 .3-2 .6 2 .6-2 .7 2 .6-2 .6 2 .7-2 .6 1 .4v2.5M98.5 195.7v3.1M111.2 188.1v2.5M111.2 195.7v3.1M126.5 195.7v3.1M169.7 193.2v2.5M184.9 190.6v2.6"/>
<path d="M245.8 180.5v2.5M342.3 193.2v2.5M98.5 200.3v3M111.2 200.3v3M111.2 208.4v2.6M126.5 200.3v3M153.8 218.6h.6M153.8 216h.6M174.2 218.6h.5M174.2 216h.5M202.1 218.6h.5M233.1 213.5v2.5"/>
<path d="M243.3 205.9v2.5M256 218.6h.6M332.2 208.4v2.6M395.7 208.4v2.6M153.8 223.7h.6M153.8 221.1h.6M164.6 231.3v2.5M174.2 223.7h.5M174.2 221.1h.5M184.9 231.3v2.5M202.1 223.7h.5M202.1 221.1h.5"/>
<path d="M202.1 226.2h.5M202.1 228.7h.5M202.1 231.3h.5M202.1 233.8h.5M202.1 236.4h.5M202.1 238.9h.5M256 223.7h.6M256 221.1h.6M256 226.2h.6M256 228.7h.6M256 231.3h.6M256 233.8h.6"/>
<path d="M256 236.4h.6M256 238.9h.6M276.3 236.4v2.5M291.5 223.7h5.1M291.5 226.2h5.1M291.5 228.7h5.1M311.9 223.7h5M311.9 226.2h5M311.9 228.7h5M360.1 233.8v2.6M365.2 223.7h5.1M365.2 221.1h5.1"/>
<path d="M365.2 226.2h5.1M365.2 228.7h5.1M383 238.9v2.5M385.5 223.7h5.1M385.5 221.1h5.1M385.5 226.2h5.1M385.5 228.7h5.1M390.6 238.9v2.5M167.1 251.6h2.6M167.1 254.1h2.6M167.1 256.7h2.6M167.1 249h2.6"/>
<path d="M172.2 248.5h2.5v1.1h-2.5zM172.2 251.1h2.5v1h-2.5zM172.2 253.6h2.5v1h-2.5zM172.2 256.2h2.5v1h-2.5zM177.3 251.6h2.5M177.3 254.1h2.5M177.3 256.7h2.5M177.3 249h2.5M202.1 251.6h.5M202.1 254.1h.5M202.1 256.7h.5M202.1 259.2h.5"/>
<path d="M202.1 241.4h.5M202.1 244h.5M202.1 246.5h.5M202.1 249h.5M223 249v2.6M230.6 249v2.6M235.7 256.7v2.5M256 251.6h.6M256 254.1h.6M256 256.7h.6M256 259.2h.6M256 241.4h.6"/>
<path d="M256 244h.6M256 246.5h.6M256 249h.6M291.5 251.6h5.1M291.5 254.1h5.1M311.9 251.6h5M311.9 254.1h5M311.9 256.7h5M372.8 259.2h2.6M375.4 256.7v.7M375.4 258.7v1M377.1 260v.2"/>
<path d="M377.4 259.5h-.3v.2M377.7 259.5h.5M378.4 259.5h.3v.2M378.7 260v.2M184.9 261.7v2.6M190 279.5v2.6M202.1 261.7h.5M202.1 264.3h.5M202.1 266.8h.5M220.4 271.9v2.5M243.3 279.5v2.6M256 261.7h.6"/>
<path d="M256 264.3h.6M256 266.8h.6M301.7 271.9v2.5M301.7 279.5v3.1M316.9 279.5v3.1M324.6 261.7v2.6M375.4 261v.7M377.1 261.2v.3h.3M377.1 260.7v.3M377.7 261.5h.5M378.7 261.2v.3h-.3M378.7 260.7v.3"/>
<path d="M179.8 294.8v2.5M190 284.6v2.5l1 .3-2 .6 2 .7-2 .6 2 .6-2 .7 2 .6-2 .6 1 .4v2.6M197.6 299.8h5M228 299.8h5.1M261.1 297.3v3.1M301.7 284.1v3M301.7 294.8v2.5M316.9 284.1v3M190 312.5v2.6M197.6 304.9h5M197.6 307.5h5M197.6 302.4h5"/>
<path d="M228 304.9h5.1M228 307.5h5.1M228 302.4h5.1M261.1 301.9v3M261.1 307.5v2.5"/>
<circle cx="255" cy="91.6" r=".99"/>
<circle cx="255" cy="89.1" r=".99"/>
<circle cx="255" cy="109.4" r=".99"/>
<circle cx="255" cy="111.9" r=".99"/>
<circle cx="152.8" cy="218.6" r=".99"/>
<circle cx="152.8" cy="216" r=".99"/>
<circle cx="173.2" cy="218.6" r=".99"/>
<circle cx="173.2" cy="216" r=".99"/>
<circle cx="201.1" cy="218.6" r=".99"/>
<circle cx="257.5" cy="218.6" r=".99"/>
<circle cx="152.8" cy="223.7" r=".99"/>
<circle cx="152.8" cy="221.1" r=".99"/>
<circle cx="173.2" cy="223.7" r=".99"/>
<circle cx="173.2" cy="221.1" r=".99"/>
<circle cx="201.1" cy="228.7" r=".99"/>
<circle cx="201.1" cy="238.9" r=".99"/>
<circle cx="201.1" cy="236.4" r=".99"/>
<circle cx="201.1" cy="226.2" r=".99"/>
<circle cx="201.1" cy="233.8" r=".99"/>
<circle cx="201.1" cy="231.3" r=".99"/>
<circle cx="201.1" cy="223.7" r=".99"/>
<circle cx="201.1" cy="221.1" r=".99"/>
<circle cx="257.5" cy="223.7" r=".99"/>
<circle cx="257.5" cy="226.2" r=".99"/>
<circle cx="257.5" cy="236.4" r=".99"/>
<circle cx="257.5" cy="228.7" r=".99"/>
<circle cx="257.5" cy="231.3" r=".99"/>
<circle cx="257.5" cy="233.8" r=".99"/>
<circle cx="257.5" cy="221.1" r=".99"/>
<circle cx="257.5" cy="238.9" r=".99"/>
<circle cx="201.1" cy="246.5" r=".99"/>
<circle cx="201.1" cy="241.4" r=".99"/>
<circle cx="201.1" cy="251.6" r=".99"/>
<circle cx="201.1" cy="249" r=".99"/>
<circle cx="201.1" cy="259.2" r=".99"/>
<circle cx="201.1" cy="254.1" r=".99"/>
<circle cx="201.1" cy="256.7" r=".99"/>
<circle cx="201.1" cy="244" r=".99"/>
<circle cx="257.5" cy="246.5" r=".99"/>
<circle cx="257.5" cy="256.7" r=".99"/>
<circle cx="257.5" cy="259.2" r=".99"/>
<circle cx="257.5" cy="241.4" r=".99"/>
<circle cx="257.5" cy="244" r=".99"/>
<circle cx="257.5" cy="251.6" r=".99"/>
<circle cx="257.5" cy="254.1" r=".99"/>
<circle cx="257.5" cy="249" r=".99"/>
<circle cx="201.1" cy="266.8" r=".99"/>
<circle cx="201.1" cy="261.7" r=".99"/>
<circle cx="201.1" cy="264.3" r=".99"/>
<circle cx="257.5" cy="264.3" r=".99"/>
<circle cx="257.5" cy="266.8" r=".99"/>
<circle cx="257.5" cy="261.7" r=".99"/>
</g>
<g fill="#c90d0c" stroke="#c90d0c" stroke-width=".22">
<path d="M274.3 47.4h4v.5h-4z"/>
<path d="M274.3 46.4h4v.5h-4z"/>
<path d="M377.4 259.7h1v1.5h-1z"/>
<path d="M172.4 248.8h1.1v.5h-1.1z"/>
<path d="M172.4 251.3h1.1v.5h-1.1z"/>
<path d="M172.4 253.9h1.1v.5h-1.1z"/>
<path d="M172.4 256.4h1.1v.5h-1.1z"/>
<path d="M162.5 141.4h4.1v.5h-4.1z"/>
<path d="M162.5 140.4h4.1v.5h-4.1z"/>
<path d="M172.7 141.4h4.1v.5h-4.1z"/>
<path d="M172.7 140.4h4.1v.5h-4.1z"/>
<path d="M190.5 138.8h4v.5h-4z"/>
<path d="M190.5 137.8h4v.5h-4z"/>
<path d="M180.3 146.5h4.1v.5h-4.1z"/>
<path d="M180.3 145.4h4.1v.5h-4.1z"/>
<path d="M292.1 47.4h4v.5h-4z"/>
<path d="M292.1 46.4h4v.5h-4z"/>
<path d="M325.1 179.5h4v.5h-4z"/>
<path d="M325.1 178.5h4v.5h-4z"/>
<path d="M261.4 45.1h.9v.1h-.9z"/>
<path d="M261.7 44.7h.2v.9h-.2z"/>
<path d="M246.1 45.1h.9v.1h-.9z"/>
<path d="M246.5 44.7h.1v.9h-.1z"/>
<path d="M109.2 199.8h4.1v.5h-4.1z"/>
<path d="M109.2 198.8h4.1v.5h-4.1z"/>
<path d="M124.4 199.8h4.1v.5h-4.1z"/>
<path d="M124.4 198.8h4.1v.5h-4.1z"/>
<path d="M96.5 199.8h4.1v.5h-4.1z"/>
<path d="M96.5 198.8h4.1v.5h-4.1z"/>
<path d="M259 301.4h4.1v.5h-4.1z"/>
<path d="M259 300.4h4.1v.5h-4.1z"/>
<path d="M160 80.4h4.1v.5h-4.1z"/>
<path d="M160 79.4h4.1v.5h-4.1z"/>
<path d="M149.8 80.4h4.1v.5h-4.1z"/>
<path d="M149.8 79.4h4.1v.5h-4.1z"/>
<path d="M299.7 283.6h4v.5h-4z"/>
<path d="M299.7 282.6h4v.5h-4z"/>
<path d="M314.9 283.6h4.1v.5h-4.1z"/>
<path d="M314.9 282.6h4.1v.5h-4.1z"/>
<path d="M230.9 45.1h.9v.1h-.9z"/>
<path d="M231.3 44.7h.1v.9h-.1z"/>
</g>
<g fill="none" stroke="#c90d0c" stroke-width=".25">
<path d="M270.5 34.5l.7-1.3 .8 1.3M186.7 54.8l.7-1.3 .8 1.3M230.6 45.9h5.1M230.7 47.7a4 4 0 0 1 4.9 0M245.8 45.9h5.1M245.9 47.7a4 4 0 0 1 5 0M261.1 45.9h5M261.2 47.7a4 4 0 0 1 4.9 0M136.6 68.7h10.2v7.7h-10.2zM174.1 62.9h1.3M174.7 63.7h5.1M176.5 62.9h1.5"/>
<path d="M179.2 62.9h1.2M266.8 61.1h3.8M127.1 86.5h3.8M150 99.2h3.8M169.7 81.4h10.1v22.9h-10.1zM344.1 95.4l.8-1.3 .8 1.3M172.8 119.5h3.8M191.7 118.3l.8-1.3 .8 1.3M314.4 114.4v5.1M315.2 113.8v1.3M315.2 116.2v1.6M315.2 118.9v1.3"/>
<path d="M377.1 113.8v1.3M377.1 116.2v1.6M377.1 118.9v1.3M377.9 114.4v5.1M207.7 127.1h25.4v48.3h-25.4zM264.2 137.3h3.9M342.3 129.7h10.2v7.6h-10.2zM137.9 150h2.5M137.9 147.5h2.5l-1.2 2.5zM167.7 150h3.9M168.4 157l1.3-1.9 1.2 1.9M176 157l1.3-1.9 1.2 1.9"/>
<path d="M314.4 150v5.1M315.2 149.4v1.2M315.2 151.8v1.5M315.2 154.5v1.2M377.1 149.4v1.2M377.1 151.8v1.5M377.1 154.5v1.2M377.9 150v5.1M137.3 160.2h3.8M110 190l1.2-1.9 1.3 1.9M168.4 195.1l1.3-1.9 1.2 1.9M183 193.2h3.8"/>
<path d="M243.9 183h3.8M340.4 195.7h3.9M109.3 211h3.8M168.4 204.6h2.5M169.7 204.6l1.2 2.6h-2.5zM169.7 203.3v1.3M169.7 207.2v1.2M231.9 215.4l1.2-1.9 1.3 1.9M241.4 205.9h3.8M330.9 210.3l1.3-1.9 1.3 1.9M370.3 218.6h15.2v12.7h-15.2zM394.4 210.3l1.3-1.9 1.2 1.9"/>
<path d="M162.7 233.8h3.8M183 233.8h3.8M274.4 238.9h3.8M296.6 221.1h15.3v10.2h-15.3zM358.2 236.4h3.8M221.7 251l1.3-2 1.2 2M229.3 251l1.3-2 1.3 2M234.4 258.6l1.3-1.9 1.2 1.9M296.6 246.5h15.3v12.7h-15.3zM381.7 240.8l1.3-1.9 1.2 1.9M389.3 240.8l1.3-1.9 1.3 1.9M183 264.3h3.8"/>
<path d="M218.5 274.4h3.8M300.4 273.8l1.3-1.9 1.3 1.9M322.7 264.3h3.8M178.5 296.7l1.3-1.9 1.3 1.9M188.7 281.4l1.3-1.9 1.2 1.9M202.6 297.3h25.4v12.7h-25.4zM242 281.4l1.3-1.9 1.3 1.9M299.8 297.3h3.8M188.1 315.1h3.8M259.2 310h3.8"/>
</g>
<path d="M249.6 86.5h7.7v7.6h-7.7zM249.6 106.8h7.7v7.6h-7.7zM150.6 213.5h7.6v12.7h-7.6zM170.9 213.5h7.6v12.7h-7.6zM198.8 216h7.7v53.4h-7.7zM252.2 216h7.6v53.4h-7.6zM169.7 247.1h7.6v11.5h-7.6z" fill="none" stroke="#c90d0c" stroke-width=".42"/>
<g fill="#c90d0c" stroke="#c90d0c" stroke-width=".22">
<path d="M374.9 260.7h1a.51 .51 0 0 1-.5 .6 .51 .51 0 0 1-.5-.6z" fill-rule="evenodd"/>
<path d="M374.9 258.2h1a.51 .51 0 0 1-.5 .5 .51 .51 0 0 1-.5-.5z" fill-rule="evenodd"/>
<path d="M375 259.8l.5-.1 .4 .5h-1z" fill-rule="evenodd"/>
<path d="M375 257.3l.5-.1 .4 .5h-1z" fill-rule="evenodd"/>
<circle cx="316.9" cy="119.5" r=".36"/>
<circle cx="316.9" cy="114.4" r=".36"/>
<circle cx="316.9" cy="155.1" r=".36"/>
<circle cx="316.9" cy="150" r=".36"/>
<circle cx="375.4" cy="119.5" r=".36"/>
<circle cx="375.4" cy="114.4" r=".36"/>
<circle cx="375.4" cy="155.1" r=".36"/>
<circle cx="375.4" cy="150" r=".36"/>
<circle cx="174.7" cy="61.1" r=".36"/>
<circle cx="179.8" cy="61.1" r=".36"/>
</g>
<g fill="none" stroke="#0dab76" stroke-width=".22">
<path d="M248.4 35.7v7.6M263.6 35.7v7.6M276.3 35.7v7.6M187.4 56v15.3h-10.1v5.1M233.1 43.3v-7.6h61v7.6M233.1 51v7.6h61v-7.6M248.4 51v7.6M263.6 51v7.6M276.3 51v7.6M129 73.8h2.6M131.6 71.3h-2.6v12.7M151.9 76.4v-2.6h15.2v40.6h10.2v-5"/>
<path d="M151.9 71.3h20.3v5.1M172.2 61.1h-10.2v15.3M174.7 66.2v10.2M182.4 61.1h5M151.9 84v12.7M162 84v27.9h10.2v-2.5M223 89.1h12.7M245.8 89.1h7.6M253.4 91.6h-7.6v5.1h-15.2M344.9 96.7v10.1M174.7 109.4v7.6M192.5 119.5v15.3h10.1"/>
<path d="M233.1 109.4h20.3M233.1 111.9h20.3M301.7 119.5h10.2M316.9 111.9v-5.1h58.5v5.1M380.4 119.5h15.3M164.6 129.7v7.6M202.6 132.2h-27.9v5.1M202.6 129.7h-63.4v2.5M238.2 134.8h10.2M238.2 129.7h10.2M238.2 132.2h10.2M238.2 139.8h10.2"/>
<path d="M238.2 137.3h10.2M266.1 139.8v2.6M301.7 134.8h35.6M316.9 122.1v25.4M337.3 132.2h-5.1v2.6M357.6 132.2h2.5v2.6M357.6 134.8h38.1M375.4 122.1v25.4M139.2 142.4v2.5M139.2 152.5v5.1M164.6 144.9v2.6h10.1v-2.6M169.7 157.6v2.6"/>
<path d="M177.3 157.6v2.6M182.4 142.4v-2.6h7.6v5.1h12.6M182.4 150h20.2M190 152.5h12.6M190 155.1h12.6M192.5 142.4h10.1M238.2 147.5h10.2M238.2 150h10.2M238.2 155.1h12.7M238.2 142.4h10.2M261.1 155.1h12.7M266.1 152.5v2.6"/>
<path d="M301.7 155.1h10.2M316.9 157.6v2.6h58.5v-2.6M380.4 155.1h15.3M169.7 170.3v2.6h32.9M177.3 170.3h25.3M190 160.2h12.6M202.6 162.7h-17.7v15.2M238.2 167.8h7.6v12.7M238.2 170.3h2.5M238.2 160.2h15.2M240.7 167.8v5.1h-2.5M316.9 170.3h35.6v2.6"/>
<path d="M327.1 170.3v5.1M342.3 160.2v12.7M98.5 195.7v-2.5h28v2.5M111.2 190.6v5.1M169.7 195.7v7.6M184.9 188.1v2.5M327.1 183v5.1M342.3 183v10.2M352.5 183v5.1h-35.6M98.5 203.3v2.6h28v-2.6M111.2 203.3v5.1M154.4 216h10.2v-5h20.3v5h-10.2"/>
<path d="M154.4 218.6h15.3M169.7 208.4v2.6M174.7 218.6h15.3M233.1 216v7.7h22.9M243.3 208.4v12.7h12.7M243.3 218.6h12.7M332.2 211v15.2h-15.3M395.7 211v10.1h-5.1M154.4 223.7h10.2v7.6M154.4 221.1h15.3M174.7 223.7h10.2v7.6M174.7 221.1h15.3"/>
<path d="M202.6 223.7h15.3M202.6 226.2h15.3M202.6 228.7h15.3M202.6 238.9h15.3M202.6 236.4h15.3M202.6 233.8h15.3M202.6 231.3h15.3M240.7 228.7h15.3M240.7 238.9h15.3M240.7 236.4h15.3M240.7 233.8h15.3M240.7 231.3h15.3"/>
<path d="M281.4 223.7h10.1M281.4 228.7h10.1M291.5 226.2h-15.2v10.2M316.9 223.7h7.7M316.9 228.7h12.7M350 223.7h15.2M350 226.2h15.2M350 221.1h15.2M365.2 228.7h-5.1v5.1M390.6 223.7h12.7M390.6 226.2h12.7M390.6 228.7h12.7"/>
<path d="M157 254.1h10.1M157 256.7h10.1M157 249h10.1M157 251.6h10.1M179.8 254.1h5.1M179.8 249h5.1v12.7M179.8 256.7h5.1M179.8 251.6h5.1M202.6 254.1h12.7M202.6 256.7h12.7M202.6 249h12.7M202.6 251.6h12.7"/>
<path d="M202.6 259.2h12.7M202.6 244h12.7M202.6 241.4h12.7M202.6 246.5h12.7M223 251.6v10.1h-20.4M230.6 251.6v15.2h-28M235.7 259.2v7.6h20.3M240.7 254.1h15.3M240.7 256.7h15.3M240.7 249h15.3M240.7 251.6h15.3M240.7 259.2h15.3"/>
<path d="M240.7 244h15.3M240.7 241.4h15.3M240.7 246.5h15.3M278.8 254.1h12.7M278.8 251.6h12.7M316.9 254.1h15.3M316.9 256.7h7.7v5M316.9 251.6h15.3M362.7 259.2h10.1M383 241.4v12.7h-7.6v2.6M390.6 241.4v22.9h-15.2v-2.6M202.6 264.3h17.8v7.6"/>
<path d="M240.7 264.3h15.3M240.7 261.7h15.3M301.7 274.4v5.1M301.7 277h15.2v2.5M179.8 297.3v7.6h17.8M190 282.1v2.5M190 294.8v5h7.6M233.1 299.8h10.2M243.3 282.1v20.3h-10.2M243.3 294.8h17.8v2.5M301.7 287.1v7.7M316.9 287.1v2.6h-15.2"/>
<path d="M184.9 302.4h12.7M197.6 307.5h-7.6v5M233.1 304.9h15.3M233.1 307.5h15.3M261.1 304.9v2.6"/>
</g>
<g fill="#0dab76" stroke="#0dab76" stroke-width=".22">
<circle cx="243.3" cy="299.8" r=".51"/>
<circle cx="243.3" cy="294.8" r=".51"/>
<circle cx="301.7" cy="277" r=".51"/>
<circle cx="268.7" cy="58.6" r=".51"/>
<circle cx="276.3" cy="58.6" r=".51"/>
<circle cx="263.6" cy="58.6" r=".51"/>
<circle cx="248.4" cy="58.6" r=".51"/>
<circle cx="243.3" cy="218.6" r=".51"/>
<circle cx="184.9" cy="251.6" r=".51"/>
<circle cx="184.9" cy="254.1" r=".51"/>
<circle cx="184.9" cy="256.7" r=".51"/>
<circle cx="169.7" cy="147.5" r=".51"/>
<circle cx="240.7" cy="167.8" r=".51"/>
<circle cx="240.7" cy="170.3" r=".51"/>
<circle cx="342.3" cy="188.1" r=".51"/>
<circle cx="327.1" cy="188.1" r=".51"/>
<circle cx="129" cy="73.8" r=".51"/>
<circle cx="111.2" cy="205.9" r=".51"/>
<circle cx="301.7" cy="289.7" r=".51"/>
<circle cx="276.3" cy="35.7" r=".51"/>
<circle cx="271.2" cy="35.7" r=".51"/>
<circle cx="263.6" cy="35.7" r=".51"/>
<circle cx="248.4" cy="35.7" r=".51"/>
<circle cx="192.5" cy="134.8" r=".51"/>
<circle cx="344.9" cy="106.8" r=".51"/>
<circle cx="187.4" cy="61.1" r=".51"/>
<circle cx="266.1" cy="155.1" r=".51"/>
<circle cx="111.2" cy="193.2" r=".51"/>
<circle cx="164.6" cy="129.7" r=".51"/>
<circle cx="342.3" cy="160.2" r=".51"/>
<circle cx="342.3" cy="170.3" r=".51"/>
<circle cx="327.1" cy="170.3" r=".51"/>
<circle cx="316.9" cy="134.8" r=".51"/>
<circle cx="332.2" cy="134.8" r=".51"/>
<circle cx="375.4" cy="134.8" r=".51"/>
<circle cx="360.1" cy="134.8" r=".51"/>
<circle cx="169.7" cy="211" r=".51"/>
<circle cx="162" cy="71.3" r=".51"/>
<circle cx="162" cy="73.8" r=".51"/>
<circle cx="151.9" cy="73.8" r=".51"/>
</g>
<use href="#words"/>
</svg>
